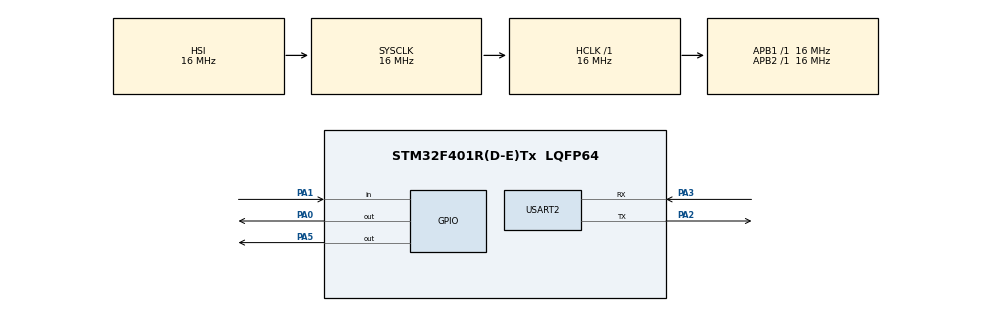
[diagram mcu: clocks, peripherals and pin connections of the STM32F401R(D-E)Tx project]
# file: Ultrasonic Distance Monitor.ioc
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Mcu.Family=STM32F4
Mcu.Name=STM32F401R(D-E)Tx
Mcu.Package=LQFP64
NVIC.PriorityGroup=NVIC_PRIORITYGROUP_4
NVIC.TIM2_IRQn=true\:0\:0\:false\:false\:true\:true\:true\:true
PA0-WKUP.Signal=GPIO_Output
PA1.Signal=GPIO_Input
PA2.Mode=Asynchronous
PA2.Signal=USART2_TX
PA3.Mode=Asynchronous
PA3.Signal=USART2_RX
PA5.Signal=GPIO_Output
ProjectManager.HeapSize=0x200
ProjectManager.StackSize=0x400
ProjectManager.TargetToolchain=STM32CubeIDE
RCC.AHBFreq_Value=16000000
RCC.APB1Freq_Value=16000000
RCC.APB2Freq_Value=16000000
RCC.CortexFreq_Value=16000000
RCC.HSE_VALUE=25000000
RCC.HSI_VALUE=16000000
RCC.LSE_VALUE=32768
RCC.SYSCLKFreq_VALUE=16000000
RCC.VCOOutputFreq_Value=192000000
TIM1.Prescaler=83
TIM2.Period=4999
TIM2.Prescaler=8399
USART2.VirtualMode=VM_ASYNC
VP_TIM1_VS_ClockSourceINT.Mode=Internal
VP_TIM2_VS_ClockSourceINT.Mode=Internal
board=custom

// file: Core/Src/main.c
/* USER CODE BEGIN Header */
/**
  ******************************************************************************
  * @file           : main.c
  * @brief          : Main program body
  ******************************************************************************
  * @attention
  *
  * Copyright (c) 2026 STMicroelectronics.
  * All rights reserved.
  *
  * This software is licensed under terms that can be found in the LICENSE file
  * in the root directory of this software component.
  * If no LICENSE file comes with this software, it is provided AS-IS.
  *
  ******************************************************************************
  */
/* USER CODE END Header */
#include "main.h"
#include <string.h>
#include <stdio.h>

TIM_HandleTypeDef htim1;
TIM_HandleTypeDef htim2;

UART_HandleTypeDef huart2;

void SystemClock_Config(void);
static void MX_GPIO_Init(void);
static void MX_TIM2_Init(void);
static void MX_USART2_UART_Init(void);
static void MX_TIM1_Init(void);

void us_delay(uint16_t us){
	  __HAL_TIM_SET_COUNTER(&htim1, 0);
	  while(__HAL_TIM_GET_COUNTER(&htim1)< us);
}

int main(void)
{

  /* MCU Configuration--------------------------------------------------------*/

  /* Reset of all peripherals, Initializes the Flash interface and the Systick. */
  HAL_Init();

  /* Configure the system clock */
  SystemClock_Config();

  /* Initialize all configured peripherals */
  MX_GPIO_Init();
  MX_TIM2_Init();
  MX_USART2_UART_Init();
  MX_TIM1_Init();
  /* USER CODE BEGIN 2 */
  HAL_TIM_Base_Start(&htim1);

  /* USER CODE END 2 */

  /* Infinite loop */
  /* USER CODE BEGIN WHILE */
  /* Timer Function for microsecond*/

  // Variables for distance sensor
  uint32_t duration;
  uint32_t start;
  uint32_t stop;
  uint32_t distance;

  // Variables for uart
  //uint8_t ch;
  char ch_buffer[50];
  //uint8_t idx = 0;

  uint8_t msg[] = "\r\nULTRASONIC DISTANCE PROJECT 1\r\n";
  HAL_UART_Transmit(&huart2, msg, sizeof(msg)-1,HAL_MAX_DELAY);

  while (1)
  {
    /* USER CODE END WHILE */

	  HAL_GPIO_WritePin(GPIOA,GPIO_PIN_0,GPIO_PIN_RESET);
	  us_delay(2);

	  //Trig goes high
	  HAL_GPIO_WritePin(GPIOA,GPIO_PIN_0, GPIO_PIN_SET);
	  us_delay(10);
	  HAL_GPIO_WritePin(GPIOA,GPIO_PIN_0,GPIO_PIN_RESET);

	  //Echo goes high
	  __HAL_TIM_SET_COUNTER(&htim1, 0);
	  while(HAL_GPIO_ReadPin(GPIOA,GPIO_PIN_1) == GPIO_PIN_RESET); //do nothing while waiting for echo to go high
	  start = __HAL_TIM_GET_COUNTER(&htim1);

	  while(HAL_GPIO_ReadPin(GPIOA,GPIO_PIN_1) == GPIO_PIN_SET); //once echo high stop timing
	  stop = __HAL_TIM_GET_COUNTER(&htim1); // get time when it goes high

	  duration = stop - start;
	  distance = (uint32_t)((duration * 0.034f)/2.0f);

	  if(distance < 10){
		  HAL_GPIO_WritePin(GPIOA,GPIO_PIN_5,GPIO_PIN_SET);
	  } else {
		  HAL_GPIO_WritePin(GPIOA,GPIO_PIN_5,GPIO_PIN_RESET);
	  }

	  sprintf(ch_buffer, "Distance: %lu cm\r\n", distance); // convert distance number into ascii
	  HAL_UART_Transmit(&huart2, (uint8_t*)ch_buffer, strlen(ch_buffer), HAL_MAX_DELAY);

	  HAL_Delay(500);

  }
}

void SystemClock_Config(void)
{
  RCC_OscInitTypeDef RCC_OscInitStruct = {0};
  RCC_ClkInitTypeDef RCC_ClkInitStruct = {0};

  /** Configure the main internal regulator output voltage
  */
  __HAL_RCC_PWR_CLK_ENABLE();
  __HAL_PWR_VOLTAGESCALING_CONFIG(PWR_REGULATOR_VOLTAGE_SCALE2);

  /** Initializes the RCC Oscillators according to the specified parameters
  * in the RCC_OscInitTypeDef structure.
  */
  RCC_OscInitStruct.OscillatorType = RCC_OSCILLATORTYPE_HSI;
  RCC_OscInitStruct.HSIState = RCC_HSI_ON;
  RCC_OscInitStruct.HSICalibrationValue = RCC_HSICALIBRATION_DEFAULT;
  RCC_OscInitStruct.PLL.PLLState = RCC_PLL_NONE;
  if (HAL_RCC_OscConfig(&RCC_OscInitStruct) != HAL_OK)
  {
    Error_Handler();
  }

  /** Initializes the CPU, AHB and APB buses clocks
  */
  RCC_ClkInitStruct.ClockType = RCC_CLOCKTYPE_HCLK|RCC_CLOCKTYPE_SYSCLK
                              |RCC_CLOCKTYPE_PCLK1|RCC_CLOCKTYPE_PCLK2;
  RCC_ClkInitStruct.SYSCLKSource = RCC_SYSCLKSOURCE_HSI;
  RCC_ClkInitStruct.AHBCLKDivider = RCC_SYSCLK_DIV1;
  RCC_ClkInitStruct.APB1CLKDivider = RCC_HCLK_DIV1;
  RCC_ClkInitStruct.APB2CLKDivider = RCC_HCLK_DIV1;

  if (HAL_RCC_ClockConfig(&RCC_ClkInitStruct, FLASH_LATENCY_0) != HAL_OK)
  {
    Error_Handler();
  }
}

static void MX_TIM1_Init(void)
{

  TIM_ClockConfigTypeDef sClockSourceConfig = {0};
  TIM_MasterConfigTypeDef sMasterConfig = {0};

  htim1.Instance = TIM1;
  htim1.Init.Prescaler = 83;
  htim1.Init.CounterMode = TIM_COUNTERMODE_UP;
  htim1.Init.Period = 65535;
  htim1.Init.ClockDivision = TIM_CLOCKDIVISION_DIV1;
  htim1.Init.RepetitionCounter = 0;
  htim1.Init.AutoReloadPreload = TIM_AUTORELOAD_PRELOAD_DISABLE;
  if (HAL_TIM_Base_Init(&htim1) != HAL_OK)
  {
    Error_Handler();
  }
  sClockSourceConfig.ClockSource = TIM_CLOCKSOURCE_INTERNAL;
  if (HAL_TIM_ConfigClockSource(&htim1, &sClockSourceConfig) != HAL_OK)
  {
    Error_Handler();
  }
  sMasterConfig.MasterOutputTrigger = TIM_TRGO_RESET;
  sMasterConfig.MasterSlaveMode = TIM_MASTERSLAVEMODE_DISABLE;
  if (HAL_TIMEx_MasterConfigSynchronization(&htim1, &sMasterConfig) != HAL_OK)
  {
    Error_Handler();
  }

}

static void MX_TIM2_Init(void)
{

  TIM_ClockConfigTypeDef sClockSourceConfig = {0};
  TIM_MasterConfigTypeDef sMasterConfig = {0};

  htim2.Instance = TIM2;
  htim2.Init.Prescaler = 8399;
  htim2.Init.CounterMode = TIM_COUNTERMODE_UP;
  htim2.Init.Period = 4999;
  htim2.Init.ClockDivision = TIM_CLOCKDIVISION_DIV1;
  htim2.Init.AutoReloadPreload = TIM_AUTORELOAD_PRELOAD_DISABLE;
  if (HAL_TIM_Base_Init(&htim2) != HAL_OK)
  {
    Error_Handler();
  }
  sClockSourceConfig.ClockSource = TIM_CLOCKSOURCE_INTERNAL;
  if (HAL_TIM_ConfigClockSource(&htim2, &sClockSourceConfig) != HAL_OK)
  {
    Error_Handler();
  }
  sMasterConfig.MasterOutputTrigger = TIM_TRGO_RESET;
  sMasterConfig.MasterSlaveMode = TIM_MASTERSLAVEMODE_DISABLE;
  if (HAL_TIMEx_MasterConfigSynchronization(&htim2, &sMasterConfig) != HAL_OK)
  {
    Error_Handler();
  }

}

static void MX_USART2_UART_Init(void)
{

  huart2.Instance = USART2;
  huart2.Init.BaudRate = 115200;
  huart2.Init.WordLength = UART_WORDLENGTH_8B;
  huart2.Init.StopBits = UART_STOPBITS_1;
  huart2.Init.Parity = UART_PARITY_NONE;
  huart2.Init.Mode = UART_MODE_TX_RX;
  huart2.Init.HwFlowCtl = UART_HWCONTROL_NONE;
  huart2.Init.OverSampling = UART_OVERSAMPLING_16;
  if (HAL_UART_Init(&huart2) != HAL_OK)
  {
    Error_Handler();
  }

}

static void MX_GPIO_Init(void)
{
  GPIO_InitTypeDef GPIO_InitStruct = {0};

  /* GPIO Ports Clock Enable */
  __HAL_RCC_GPIOC_CLK_ENABLE();
  __HAL_RCC_GPIOA_CLK_ENABLE();

  /*Configure GPIO pin Output Level */
  HAL_GPIO_WritePin(GPIOC, GPIO_PIN_0, GPIO_PIN_RESET);

  /*Configure GPIO pin Output Level */
  HAL_GPIO_WritePin(GPIOA, GPIO_PIN_5, GPIO_PIN_RESET);

  /*Configure GPIO pin : PC0 */
  GPIO_InitStruct.Pin = GPIO_PIN_0;
  GPIO_InitStruct.Mode = GPIO_MODE_OUTPUT_PP;
  GPIO_InitStruct.Pull = GPIO_NOPULL;
  GPIO_InitStruct.Speed = GPIO_SPEED_FREQ_LOW;
  HAL_GPIO_Init(GPIOC, &GPIO_InitStruct);

  /*Configure GPIO pin : PC1 */
  GPIO_InitStruct.Pin = GPIO_PIN_1;
  GPIO_InitStruct.Mode = GPIO_MODE_INPUT;
  GPIO_InitStruct.Pull = GPIO_NOPULL;
  HAL_GPIO_Init(GPIOC, &GPIO_InitStruct);

  /*Configure GPIO pin : PA5 */
  GPIO_InitStruct.Pin = GPIO_PIN_5;
  GPIO_InitStruct.Mode = GPIO_MODE_OUTPUT_PP;
  GPIO_InitStruct.Pull = GPIO_NOPULL;
  GPIO_InitStruct.Speed = GPIO_SPEED_FREQ_LOW;
  HAL_GPIO_Init(GPIOA, &GPIO_InitStruct);

}

void Error_Handler(void)
{
  __disable_irq();
  while (1)
  {
  }
}
